VERSION 5.7 ;
  NOWIREEXTENSIONATPIN ON ;
  DIVIDERCHAR "/" ;
  BUSBITCHARS "[]" ;
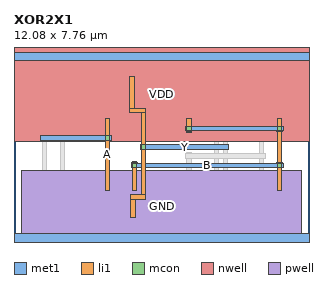
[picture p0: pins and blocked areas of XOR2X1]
MACRO XOR2X1
  CLASS CORE ;
  FOREIGN XOR2X1 ;
  ORIGIN 0.000 0.000 ;
  SIZE 12.080 BY 7.760 ;
  SYMMETRY X Y ;
  SITE unitrh ;
  PIN Y
    DIRECTION OUTPUT ;
    USE SIGNAL ;
    ANTENNADIFFAREA 1.543800 ;
    PORT
      LAYER met1 ;
        RECT 5.185 3.965 5.415 3.995 ;
        RECT 8.515 3.965 8.745 3.995 ;
        RECT 5.155 3.795 8.775 3.965 ;
        RECT 5.185 3.765 5.415 3.795 ;
        RECT 8.515 3.765 8.745 3.795 ;
    END
    PORT
      LAYER li1 ;
        RECT 4.735 5.470 4.905 6.740 ;
        RECT 4.735 5.300 5.385 5.470 ;
        RECT 5.215 1.920 5.385 5.300 ;
        RECT 4.775 1.750 5.385 1.920 ;
        RECT 4.775 1.020 4.945 1.750 ;
      LAYER mcon ;
        RECT 5.215 3.795 5.385 3.965 ;
    END
  END Y
  PIN A
    DIRECTION INPUT ;
    USE SIGNAL ;
    ANTENNAGATEAREA 2.060500 ;
    PORT
      LAYER met1 ;
        RECT 1.115 4.335 1.345 4.365 ;
        RECT 3.705 4.335 3.935 4.365 ;
        RECT 1.085 4.165 3.965 4.335 ;
        RECT 1.115 4.135 1.345 4.165 ;
        RECT 3.705 4.135 3.935 4.165 ;
    END
    PORT
      LAYER li1 ;
        RECT 3.735 2.100 3.905 5.045 ;
      LAYER mcon ;
        RECT 3.735 4.165 3.905 4.335 ;
    END
  END A
  PIN B
    DIRECTION INPUT ;
    USE SIGNAL ;
    ANTENNAGATEAREA 2.054500 ;
    PORT
      LAYER met1 ;
        RECT 7.035 4.705 7.265 4.735 ;
        RECT 10.735 4.705 10.965 4.735 ;
        RECT 7.005 4.535 10.995 4.705 ;
        RECT 7.035 4.505 7.265 4.535 ;
        RECT 10.735 4.505 10.965 4.535 ;
        RECT 4.815 3.225 5.045 3.255 ;
        RECT 10.735 3.225 10.965 3.255 ;
        RECT 4.785 3.055 10.995 3.225 ;
        RECT 4.815 3.025 5.045 3.055 ;
        RECT 10.735 3.025 10.965 3.055 ;
    END
    PORT
      LAYER li1 ;
        RECT 10.765 2.100 10.935 5.045 ;
      LAYER mcon ;
        RECT 10.765 4.535 10.935 4.705 ;
        RECT 10.765 3.055 10.935 3.225 ;
    END
    PORT
      LAYER li1 ;
        RECT 7.065 4.455 7.235 5.045 ;
      LAYER mcon ;
        RECT 7.065 4.535 7.235 4.705 ;
    END
    PORT
      LAYER li1 ;
        RECT 4.845 2.100 5.015 3.305 ;
      LAYER mcon ;
        RECT 4.845 3.055 5.015 3.225 ;
    END
  END B
  PIN VDD
    DIRECTION INOUT ;
    USE POWER ;
    SHAPE ABUTMENT ;
    PORT
      LAYER nwell ;
        RECT 0.000 4.110 12.080 7.940 ;
      LAYER met1 ;
        RECT 0.000 7.410 12.080 7.760 ;
    END
  END VDD
  PIN GND
    DIRECTION INOUT ;
    USE GROUND ;
    SHAPE ABUTMENT ;
    PORT
      LAYER pwell ;
        RECT 0.320 0.000 11.760 2.900 ;
      LAYER met1 ;
        RECT 0.000 0.000 12.080 0.350 ;
    END
  END GND
  OBS
      LAYER li1 ;
        RECT 0.000 7.410 12.080 7.760 ;
        RECT 0.320 4.290 0.660 7.410 ;
        RECT 1.080 5.365 1.250 7.410 ;
        RECT 0.320 0.350 0.660 2.900 ;
        RECT 1.145 2.100 1.315 5.045 ;
        RECT 1.520 4.845 1.690 7.200 ;
        RECT 1.960 5.365 2.130 7.410 ;
        RECT 1.520 4.675 2.055 4.845 ;
        RECT 1.885 2.345 2.055 4.675 ;
        RECT 2.540 4.290 2.880 7.410 ;
        RECT 3.415 5.470 3.585 7.080 ;
        RECT 3.855 5.730 4.025 7.410 ;
        RECT 4.295 7.000 5.345 7.170 ;
        RECT 4.295 5.470 4.465 7.000 ;
        RECT 5.175 5.730 5.345 7.000 ;
        RECT 3.415 5.300 4.465 5.470 ;
        RECT 4.845 4.085 5.015 5.045 ;
        RECT 5.870 4.290 6.210 7.410 ;
        RECT 6.745 5.470 6.915 7.080 ;
        RECT 7.185 5.730 7.355 7.410 ;
        RECT 7.625 7.000 8.675 7.170 ;
        RECT 7.625 5.470 7.795 7.000 ;
        RECT 6.745 5.300 7.795 5.470 ;
        RECT 8.065 5.470 8.235 6.740 ;
        RECT 8.505 5.730 8.675 7.000 ;
        RECT 8.065 5.300 8.715 5.470 ;
        RECT 1.515 2.175 2.055 2.345 ;
        RECT 1.035 0.800 1.205 1.930 ;
        RECT 1.515 1.020 1.685 2.175 ;
        RECT 2.005 0.800 2.175 1.930 ;
        RECT 1.035 0.630 2.175 0.800 ;
        RECT 1.035 0.350 1.205 0.630 ;
        RECT 1.520 0.350 1.690 0.630 ;
        RECT 2.005 0.350 2.175 0.630 ;
        RECT 2.540 0.350 2.880 2.900 ;
        RECT 3.320 1.850 3.490 1.930 ;
        RECT 4.290 1.850 4.460 1.930 ;
        RECT 3.320 1.680 4.460 1.850 ;
        RECT 3.320 0.550 3.490 1.680 ;
        RECT 3.805 0.350 3.975 1.305 ;
        RECT 4.290 0.800 4.460 1.680 ;
        RECT 5.260 0.800 5.430 1.570 ;
        RECT 4.290 0.630 5.430 0.800 ;
        RECT 4.290 0.550 4.460 0.630 ;
        RECT 5.260 0.550 5.430 0.630 ;
        RECT 5.870 0.350 6.210 2.900 ;
        RECT 7.065 2.100 7.235 3.675 ;
        RECT 8.175 2.100 8.345 5.045 ;
        RECT 6.650 1.850 6.820 1.930 ;
        RECT 7.620 1.850 7.790 1.930 ;
        RECT 8.545 1.920 8.715 5.300 ;
        RECT 9.200 4.290 9.540 7.410 ;
        RECT 9.950 5.365 10.120 7.410 ;
        RECT 10.390 4.845 10.560 7.200 ;
        RECT 10.830 5.365 11.000 7.410 ;
        RECT 10.025 4.675 10.560 4.845 ;
        RECT 6.650 1.680 7.790 1.850 ;
        RECT 6.650 0.550 6.820 1.680 ;
        RECT 7.135 0.350 7.305 1.305 ;
        RECT 7.620 0.800 7.790 1.680 ;
        RECT 8.105 1.750 8.715 1.920 ;
        RECT 8.105 1.020 8.275 1.750 ;
        RECT 8.590 0.800 8.760 1.570 ;
        RECT 7.620 0.630 8.760 0.800 ;
        RECT 7.620 0.550 7.790 0.630 ;
        RECT 8.590 0.550 8.760 0.630 ;
        RECT 9.200 0.350 9.540 2.900 ;
        RECT 10.025 2.345 10.195 4.675 ;
        RECT 11.420 4.290 11.760 7.410 ;
        RECT 10.025 2.175 10.565 2.345 ;
        RECT 9.905 0.800 10.075 1.930 ;
        RECT 10.395 1.020 10.565 2.175 ;
        RECT 10.875 0.800 11.045 1.930 ;
        RECT 9.905 0.630 11.045 0.800 ;
        RECT 9.905 0.350 10.075 0.630 ;
        RECT 10.390 0.350 10.560 0.630 ;
        RECT 10.875 0.350 11.045 0.630 ;
        RECT 11.420 0.350 11.760 2.900 ;
        RECT 0.000 0.000 12.080 0.350 ;
      LAYER mcon ;
        RECT 0.775 7.495 0.945 7.665 ;
        RECT 1.145 7.495 1.315 7.665 ;
        RECT 1.515 7.495 1.685 7.665 ;
        RECT 1.885 7.495 2.055 7.665 ;
        RECT 2.255 7.495 2.425 7.665 ;
        RECT 2.995 7.495 3.165 7.665 ;
        RECT 3.365 7.495 3.535 7.665 ;
        RECT 3.735 7.495 3.905 7.665 ;
        RECT 4.105 7.495 4.275 7.665 ;
        RECT 4.475 7.495 4.645 7.665 ;
        RECT 4.845 7.495 5.015 7.665 ;
        RECT 5.215 7.495 5.385 7.665 ;
        RECT 5.585 7.495 5.755 7.665 ;
        RECT 6.325 7.495 6.495 7.665 ;
        RECT 6.695 7.495 6.865 7.665 ;
        RECT 7.065 7.495 7.235 7.665 ;
        RECT 7.435 7.495 7.605 7.665 ;
        RECT 7.805 7.495 7.975 7.665 ;
        RECT 8.175 7.495 8.345 7.665 ;
        RECT 8.545 7.495 8.715 7.665 ;
        RECT 8.915 7.495 9.085 7.665 ;
        RECT 9.655 7.495 9.825 7.665 ;
        RECT 10.025 7.495 10.195 7.665 ;
        RECT 10.395 7.495 10.565 7.665 ;
        RECT 10.765 7.495 10.935 7.665 ;
        RECT 11.135 7.495 11.305 7.665 ;
        RECT 1.145 4.165 1.315 4.335 ;
        RECT 4.845 4.165 5.015 4.335 ;
        RECT 7.065 3.425 7.235 3.595 ;
        RECT 1.885 2.685 2.055 2.855 ;
        RECT 8.175 2.685 8.345 2.855 ;
        RECT 8.545 3.795 8.715 3.965 ;
        RECT 10.025 4.165 10.195 4.335 ;
        RECT 10.025 3.425 10.195 3.595 ;
        RECT 0.775 0.095 0.945 0.265 ;
        RECT 1.145 0.095 1.315 0.265 ;
        RECT 1.515 0.095 1.685 0.265 ;
        RECT 1.885 0.095 2.055 0.265 ;
        RECT 2.255 0.095 2.425 0.265 ;
        RECT 2.995 0.095 3.165 0.265 ;
        RECT 3.365 0.095 3.535 0.265 ;
        RECT 3.735 0.095 3.905 0.265 ;
        RECT 4.105 0.095 4.275 0.265 ;
        RECT 4.475 0.095 4.645 0.265 ;
        RECT 4.845 0.095 5.015 0.265 ;
        RECT 5.215 0.095 5.385 0.265 ;
        RECT 5.585 0.095 5.755 0.265 ;
        RECT 6.325 0.095 6.495 0.265 ;
        RECT 6.695 0.095 6.865 0.265 ;
        RECT 7.065 0.095 7.235 0.265 ;
        RECT 7.435 0.095 7.605 0.265 ;
        RECT 7.805 0.095 7.975 0.265 ;
        RECT 8.175 0.095 8.345 0.265 ;
        RECT 8.545 0.095 8.715 0.265 ;
        RECT 8.915 0.095 9.085 0.265 ;
        RECT 9.655 0.095 9.825 0.265 ;
        RECT 10.025 0.095 10.195 0.265 ;
        RECT 10.395 0.095 10.565 0.265 ;
        RECT 10.765 0.095 10.935 0.265 ;
        RECT 11.135 0.095 11.305 0.265 ;
      LAYER met1 ;
        RECT 4.815 4.335 5.045 4.365 ;
        RECT 9.995 4.335 10.225 4.365 ;
        RECT 4.785 4.165 10.255 4.335 ;
        RECT 4.815 4.135 5.045 4.165 ;
        RECT 9.995 4.135 10.225 4.165 ;
        RECT 7.035 3.595 7.265 3.625 ;
        RECT 9.995 3.595 10.225 3.625 ;
        RECT 7.005 3.425 10.255 3.595 ;
        RECT 7.035 3.395 7.265 3.425 ;
        RECT 9.995 3.395 10.225 3.425 ;
        RECT 1.855 2.855 2.085 2.885 ;
        RECT 8.145 2.855 8.375 2.885 ;
        RECT 1.825 2.685 8.405 2.855 ;
        RECT 1.855 2.655 2.085 2.685 ;
        RECT 8.145 2.655 8.375 2.685 ;
  END
END XOR2X1
END LIBRARY

